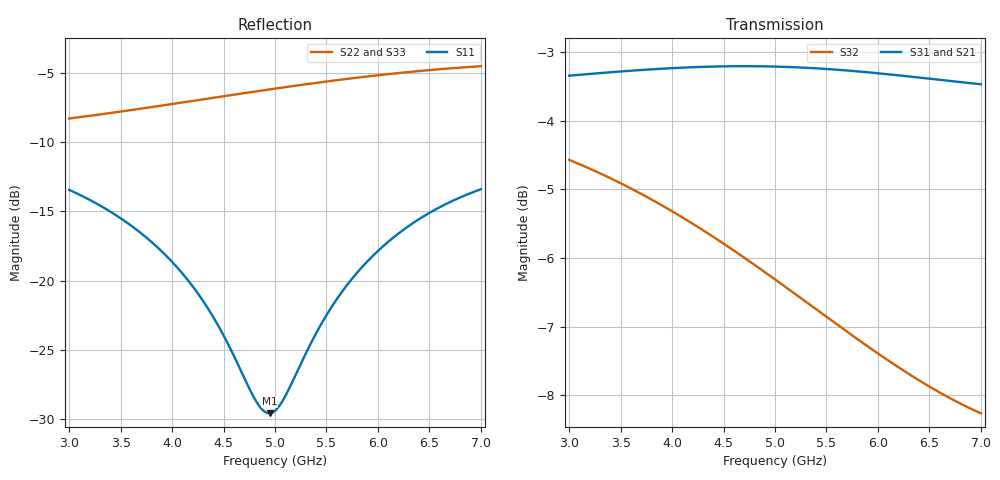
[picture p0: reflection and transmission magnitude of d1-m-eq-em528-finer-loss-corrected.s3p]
! yapnr Order 0 prediction d1-m-eq-em528-finer: predictions/D1/variants/d1-star-m-eq-em528/finer.s3p, loss-corrected
! substrate M-eq-em528; coupon model OSHPARK-4L-EM528; correction: ratio (port line)
! |S21|, |S31| (and S12, S13) scaled, phases kept; 50 ohm, e^(+jwt)
# GHz S RI R 50
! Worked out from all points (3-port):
!   161 points, 3 GHz to 7 GHz, reference 50 ohm
!   strongest paths, dB at 3 GHz, 4 GHz, 5 GHz, 6 GHz, 7 GHz:
!     S31: -3.3, -3.2, -3.2, -3.3, -3.5
!     S21: -3.3, -3.2, -3.2, -3.3, -3.5
!     S32: -4.6, -5.3, -6.3, -7.4, -8.3
!   lowest |S11| = -29.6 dB at 4.95 GHz (marker M1), VSWR 1.07, Z = 46.8 + j0.328 ohm
!   |S11| at or under -10 dB: start of sweep to end of sweep
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3  -0.1468 0.1541  0.0846 -0.6751  0.0846 -0.6751
   0.0845 -0.6751  0.0757 0.3778  -0.1723 -0.5651
   0.0845 -0.6751  -0.1723 -0.5651  0.0757 0.3778
4.05  -0.0563 0.0962  -0.27 -0.6343  -0.27 -0.6343
      -0.27 -0.6342  0.3285 0.2891  -0.4317 -0.3232
      -0.27 -0.6342  -0.4317 -0.3232  0.3285 0.2891
4.4  -0.0391 0.0626  -0.3791 -0.5776  -0.3791 -0.5776
     -0.379 -0.5775  0.4002 0.2225  -0.47 -0.2209
     -0.379 -0.5775  -0.47 -0.2209  0.4002 0.2225
4.825  -0.0319 0.0171  -0.4951 -0.4824  -0.4951 -0.4824
       -0.4951 -0.4823  0.4684 0.1202  -0.4842 -0.0979
       -0.4951 -0.4823  -0.4842 -0.0979  0.4684 0.1202
4.95  -0.0329 0.0035  -0.5248 -0.4495  -0.5248 -0.4495
      -0.5248 -0.4495  0.4836 0.0865  -0.4824 -0.0634
      -0.5248 -0.4495  -0.4824 -0.0634  0.4836 0.0865
5  -0.0337 -0.00189  -0.5361 -0.4358  -0.5361 -0.4358
   -0.536 -0.4358  0.489 0.0726  -0.4809 -0.0499
   -0.536 -0.4358  -0.4809 -0.0499  0.489 0.0726
5.5  -0.0545 -0.0515  -0.6265 -0.2847  -0.6265 -0.2847
     -0.6264 -0.2846  0.5192 -0.0749  -0.4482 0.0732
     -0.6264 -0.2846  -0.4482 0.0732  0.5192 -0.0749
5.875  -0.0831 -0.0794  -0.6657 -0.1597  -0.6657 -0.1597
       -0.6656 -0.1596  0.512 -0.1894  -0.4071 0.149
       -0.6656 -0.1596  -0.4071 0.149  0.512 -0.1894
6.375  -0.1324 -0.0976  -0.6785 0.0115  -0.6785 0.0115
       -0.6784 0.0116  0.463 -0.3345  -0.3402 0.2276
       -0.6784 0.0116  -0.3402 0.2276  0.463 -0.3345
7  -0.1966 -0.0841  -0.635 0.2159  -0.635 0.2159
   -0.6348 0.216  0.3482 -0.4837  -0.2492 0.2952
   -0.6348 0.216  -0.2492 0.2952  0.3482 -0.4837
